# W18 power abstract: 1/4 of the W10 p5 pair: its M6 VDD/VSS straps (5.4 um per net), OBS M1-M5; M7 open for the cluster straps (the pair must be re-hardened with M7 power pins, W18 finding)
VERSION 5.8 ;
BUSBITCHARS "[]" ;
DIVIDERCHAR "/" ;
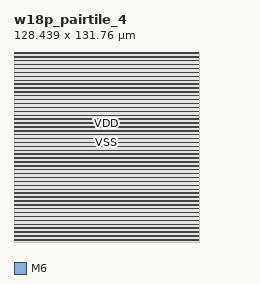
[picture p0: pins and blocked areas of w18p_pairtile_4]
MACRO w18p_pairtile_4
  CLASS BLOCK ;
  FOREIGN w18p_pairtile_4 0 0 ;
  SYMMETRY X Y ;
  SIZE 128.439 BY 131.760 ;
  PIN VDD
    DIRECTION INOUT ;
    USE POWER ;
    PORT
      LAYER M6 ;
        RECT 0.500 1.350 127.939 1.638 ;
        RECT 0.500 6.750 127.939 7.038 ;
        RECT 0.500 12.150 127.939 12.438 ;
        RECT 0.500 17.550 127.939 17.838 ;
        RECT 0.500 22.950 127.939 23.238 ;
        RECT 0.500 28.350 127.939 28.638 ;
        RECT 0.500 33.750 127.939 34.038 ;
        RECT 0.500 39.150 127.939 39.438 ;
        RECT 0.500 44.550 127.939 44.838 ;
        RECT 0.500 49.950 127.939 50.238 ;
        RECT 0.500 55.350 127.939 55.638 ;
        RECT 0.500 60.750 127.939 61.038 ;
        RECT 0.500 66.150 127.939 66.438 ;
        RECT 0.500 71.550 127.939 71.838 ;
        RECT 0.500 76.950 127.939 77.238 ;
        RECT 0.500 82.350 127.939 82.638 ;
        RECT 0.500 87.750 127.939 88.038 ;
        RECT 0.500 93.150 127.939 93.438 ;
        RECT 0.500 98.550 127.939 98.838 ;
        RECT 0.500 103.950 127.939 104.238 ;
        RECT 0.500 109.350 127.939 109.638 ;
        RECT 0.500 114.750 127.939 115.038 ;
        RECT 0.500 120.150 127.939 120.438 ;
        RECT 0.500 125.550 127.939 125.838 ;
        RECT 0.500 130.950 127.939 131.238 ;
    END
  END VDD
  PIN VSS
    DIRECTION INOUT ;
    USE GROUND ;
    PORT
      LAYER M6 ;
        RECT 0.500 4.050 127.939 4.338 ;
        RECT 0.500 9.450 127.939 9.738 ;
        RECT 0.500 14.850 127.939 15.138 ;
        RECT 0.500 20.250 127.939 20.538 ;
        RECT 0.500 25.650 127.939 25.938 ;
        RECT 0.500 31.050 127.939 31.338 ;
        RECT 0.500 36.450 127.939 36.738 ;
        RECT 0.500 41.850 127.939 42.138 ;
        RECT 0.500 47.250 127.939 47.538 ;
        RECT 0.500 52.650 127.939 52.938 ;
        RECT 0.500 58.050 127.939 58.338 ;
        RECT 0.500 63.450 127.939 63.738 ;
        RECT 0.500 68.850 127.939 69.138 ;
        RECT 0.500 74.250 127.939 74.538 ;
        RECT 0.500 79.650 127.939 79.938 ;
        RECT 0.500 85.050 127.939 85.338 ;
        RECT 0.500 90.450 127.939 90.738 ;
        RECT 0.500 95.850 127.939 96.138 ;
        RECT 0.500 101.250 127.939 101.538 ;
        RECT 0.500 106.650 127.939 106.938 ;
        RECT 0.500 112.050 127.939 112.338 ;
        RECT 0.500 117.450 127.939 117.738 ;
        RECT 0.500 122.850 127.939 123.138 ;
        RECT 0.500 128.250 127.939 128.538 ;
    END
  END VSS
  OBS
    LAYER M1 ;
      RECT 0 0 128.439 131.760 ;
    LAYER M2 ;
      RECT 0 0 128.439 131.760 ;
    LAYER M3 ;
      RECT 0 0 128.439 131.760 ;
    LAYER M4 ;
      RECT 0 0 128.439 131.760 ;
    LAYER M5 ;
      RECT 0 0 128.439 131.760 ;
  END
END w18p_pairtile_4
END LIBRARY
